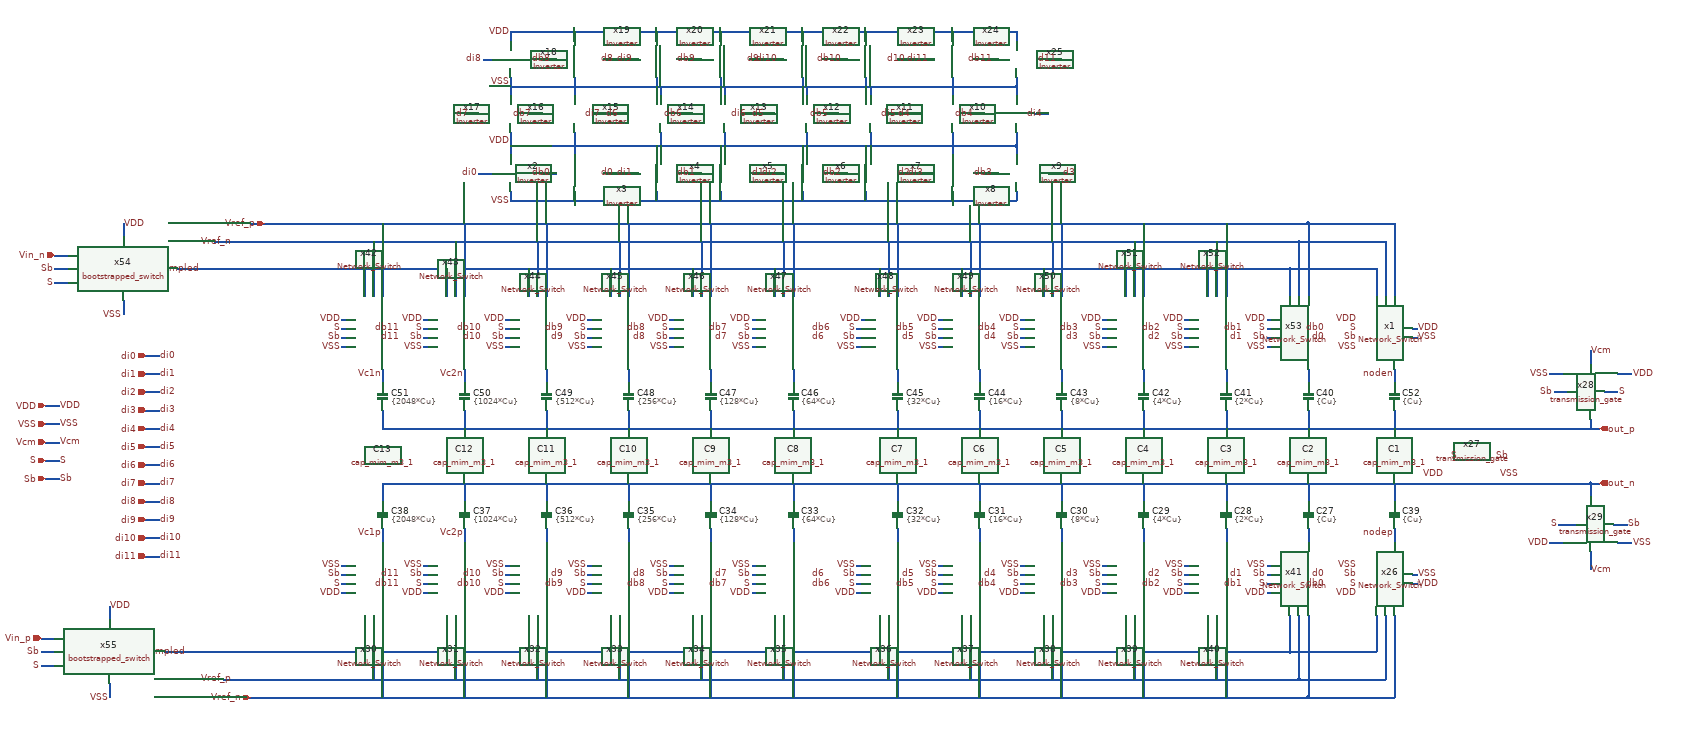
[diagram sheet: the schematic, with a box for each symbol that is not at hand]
v {xschem version=3.4.8RC file_version=1.2}
G {}
K {}
V {}
S {}
E {}
N -970 310 -970 340 {lab=out_n}
N -710 310 10 310 {lab=out_n}
N 90 310 810 310 {lab=out_n}
N 1060 310 1060 340 {lab=out_n}
N 880 310 880 340 {lab=out_n}
N 700 310 700 340 {lab=out_n}
N 520 310 520 340 {lab=out_n}
N 340 310 340 340 {lab=out_n}
N 160 310 160 340 {lab=out_n}
N -70 310 -70 340 {lab=out_n}
N -250 310 -250 340 {lab=out_n}
N -430 310 -430 340 {lab=out_n}
N -610 310 -610 340 {lab=out_n}
N -790 310 -790 340 {lab=out_n}
N -970 160 -970 190 {lab=out_p}
N -710 190 10 190 {lab=out_p}
N 90 190 810 190 {lab=out_p}
N 340 160 340 190 {lab=out_p}
N 160 160 160 190 {lab=out_p}
N -70 160 -70 190 {lab=out_p}
N -250 160 -250 190 {lab=out_p}
N -430 160 -430 190 {lab=out_p}
N -610 160 -610 190 {lab=out_p}
N -790 160 -790 190 {lab=out_p}
N -840 310 -710 310 {lab=out_n}
N -970 310 -840 310 {lab=out_n}
N 810 310 1530 310 {lab=out_n}
N 810 190 1530 190 {lab=out_p}
N -970 420 -970 440 {lab=Vc1p}
N -790 420 -790 440 {lab=Vc2p}
N -970 190 -710 190 {lab=out_p}
N 1060 60 1060 80 {lab=#net1}
N 880 60 880 80 {lab=#net2}
N 700 60 700 80 {lab=#net3}
N 520 60 520 80 {lab=#net4}
N 340 60 340 80 {lab=#net5}
N 160 60 160 80 {lab=#net6}
N -70 60 -70 80 {lab=#net7}
N -250 60 -250 80 {lab=#net8}
N -430 60 -430 80 {lab=#net9}
N -610 60 -610 80 {lab=#net10}
N -790 60 -790 80 {lab=Vc2n}
N -970 60 -970 80 {lab=Vc1n}
N -1010 -160 1020 -160 {lab=in_n_sampled}
N 1020 -160 1020 -100 {lab=in_n_sampled}
N 840 -160 840 -100 {lab=in_n_sampled}
N 660 -160 660 -100 {lab=in_n_sampled}
N 480 -160 480 -100 {lab=in_n_sampled}
N 300 -160 300 -100 {lab=in_n_sampled}
N 120 -160 120 -100 {lab=in_n_sampled}
N -1110 680 1020 680 {lab=in_p_sampled}
N 1020 600 1020 680 {lab=in_p_sampled}
N 840 600 840 680 {lab=in_p_sampled}
N 660 600 660 680 {lab=in_p_sampled}
N 480 600 480 680 {lab=in_p_sampled}
N 300 600 300 680 {lab=in_p_sampled}
N 120 600 120 680 {lab=in_p_sampled}
N -1710 180 -1680 180 {lab=VSS}
N -1710 140 -1680 140 {lab=VDD}
N -1710 260 -1680 260 {lab=S}
N -1710 300 -1680 300 {lab=Sb}
N -1490 150 -1460 150 {lab=di3}
N -1710 220 -1680 220 {lab=Vcm}
N -1540 -260 -1540 -230 {lab=VDD}
N -1570 580 -1570 610 {lab=VDD}
N -1060 -50 -1050 -50 {lab=VDD}
N -880 -50 -870 -50 {lab=VDD}
N -700 -50 -690 -50 {lab=VDD}
N -520 -50 -510 -50 {lab=VDD}
N -340 -50 -330 -50 {lab=VDD}
N -160 -50 -150 -50 {lab=VDD}
N 80 -50 90 -50 {lab=VDD}
N 250 -50 260 -50 {lab=VDD}
N 430 -50 440 -50 {lab=VDD}
N 610 -50 620 -50 {lab=VDD}
N 790 -50 800 -50 {lab=VDD}
N 970 -50 980 -50 {lab=VDD}
N -1060 550 -1050 550 {lab=VDD}
N -880 550 -870 550 {lab=VDD}
N -700 550 -690 550 {lab=VDD}
N -520 550 -510 550 {lab=VDD}
N -340 550 -330 550 {lab=VDD}
N -160 550 -150 550 {lab=VDD}
N 70 550 80 550 {lab=VDD}
N 250 550 260 550 {lab=VDD}
N 430 550 440 550 {lab=VDD}
N 790 550 800 550 {lab=VDD}
N 610 550 620 550 {lab=VDD}
N 970 550 980 550 {lab=VDD}
N -1540 -90 -1540 -60 {lab=VSS}
N -1570 750 -1570 780 {lab=VSS}
N -1060 490 -1050 490 {lab=VSS}
N -880 490 -870 490 {lab=VSS}
N -700 490 -690 490 {lab=VSS}
N -520 490 -510 490 {lab=VSS}
N -340 490 -330 490 {lab=VSS}
N -160 490 -150 490 {lab=VSS}
N 70 490 80 490 {lab=VSS}
N 250 490 260 490 {lab=VSS}
N 430 490 440 490 {lab=VSS}
N 610 490 620 490 {lab=VSS}
N 790 490 800 490 {lab=VSS}
N 970 490 980 490 {lab=VSS}
N -1060 10 -1050 10 {lab=VSS}
N -880 10 -870 10 {lab=VSS}
N -700 10 -690 10 {lab=VSS}
N -520 10 -510 10 {lab=VSS}
N -340 10 -330 10 {lab=VSS}
N -160 10 -150 10 {lab=VSS}
N 70 10 80 10 {lab=VSS}
N 250 10 260 10 {lab=VSS}
N 430 10 440 10 {lab=VSS}
N 610 10 620 10 {lab=VSS}
N 790 10 800 10 {lab=VSS}
N 970 10 980 10 {lab=VSS}
N -1090 -220 1040 -220 {lab=Vref_n}
N 1040 -220 1040 -100 {lab=Vref_n}
N 1060 -260 1060 -100 {lab=Vref_p}
N -1110 -260 1060 -260 {lab=Vref_p}
N -990 -220 -990 -100 {lab=Vref_n}
N -970 -260 -970 -100 {lab=Vref_p}
N -810 -220 -810 -100 {lab=Vref_n}
N -790 -260 -790 -100 {lab=Vref_p}
N -630 -220 -630 -100 {lab=Vref_n}
N -610 -260 -610 -100 {lab=Vref_p}
N -450 -220 -450 -100 {lab=Vref_n}
N -430 -260 -430 -100 {lab=Vref_p}
N -270 -220 -270 -100 {lab=Vref_n}
N -250 -260 -250 -100 {lab=Vref_p}
N -90 -220 -90 -100 {lab=Vref_n}
N -70 -260 -70 -100 {lab=Vref_p}
N 140 -220 140 -100 {lab=Vref_n}
N 160 -260 160 -100 {lab=Vref_p}
N 320 -220 320 -100 {lab=Vref_n}
N 340 -260 340 -100 {lab=Vref_p}
N 500 -220 500 -100 {lab=Vref_n}
N 520 -260 520 -100 {lab=Vref_p}
N 680 -220 680 -100 {lab=Vref_n}
N 700 -260 700 -100 {lab=Vref_p}
N 860 -220 860 -100 {lab=Vref_n}
N 880 -260 880 -100 {lab=Vref_p}
N 1040 600 1040 740 {lab=Vref_p}
N -1090 740 1040 740 {lab=Vref_p}
N 1060 600 1060 780 {lab=Vref_n}
N -1110 780 1060 780 {lab=Vref_n}
N -990 600 -990 740 {lab=Vref_p}
N -970 600 -970 780 {lab=Vref_n}
N -810 600 -810 740 {lab=Vref_p}
N -790 600 -790 780 {lab=Vref_n}
N -630 600 -630 740 {lab=Vref_p}
N -610 600 -610 780 {lab=Vref_n}
N -450 600 -450 740 {lab=Vref_p}
N -430 600 -430 780 {lab=Vref_n}
N -270 600 -270 740 {lab=Vref_p}
N -250 600 -250 780 {lab=Vref_n}
N -90 600 -90 740 {lab=Vref_p}
N -70 600 -70 780 {lab=Vref_n}
N 140 600 140 740 {lab=Vref_p}
N 160 600 160 780 {lab=Vref_n}
N 320 600 320 740 {lab=Vref_p}
N 340 600 340 780 {lab=Vref_n}
N 500 600 500 740 {lab=Vref_p}
N 520 600 520 780 {lab=Vref_n}
N 680 600 680 740 {lab=Vref_p}
N 700 600 700 780 {lab=Vref_n}
N 860 600 860 740 {lab=Vref_p}
N 880 600 880 780 {lab=Vref_n}
N -1490 30 -1460 30 {lab=di0}
N -1490 70 -1460 70 {lab=di1}
N -1490 110 -1460 110 {lab=di2}
N -1490 230 -1460 230 {lab=di5}
N -1490 190 -1460 190 {lab=di4}
N -1490 310 -1460 310 {lab=di7}
N -1490 270 -1460 270 {lab=di6}
N -1490 390 -1460 390 {lab=di9}
N -1490 350 -1460 350 {lab=di8}
N -1490 470 -1460 470 {lab=di11}
N -1490 430 -1460 430 {lab=di10}
N -1060 -30 -1050 -30 {lab=S}
N -1060 -10 -1050 -10 {lab=Sb}
N -880 -30 -870 -30 {lab=S}
N -880 -10 -870 -10 {lab=Sb}
N -700 -30 -690 -30 {lab=S}
N -700 -10 -690 -10 {lab=Sb}
N -520 -30 -510 -30 {lab=S}
N -520 -10 -510 -10 {lab=Sb}
N -340 -30 -330 -30 {lab=S}
N -340 -10 -330 -10 {lab=Sb}
N -160 -30 -150 -30 {lab=S}
N -160 -10 -150 -10 {lab=Sb}
N 70 -30 80 -30 {lab=S}
N 70 -10 80 -10 {lab=Sb}
N 250 -30 260 -30 {lab=S}
N 250 -10 260 -10 {lab=Sb}
N 430 -30 440 -30 {lab=S}
N 430 -10 440 -10 {lab=Sb}
N 610 -30 620 -30 {lab=S}
N 610 -10 620 -10 {lab=Sb}
N 790 -30 800 -30 {lab=S}
N 790 -10 800 -10 {lab=Sb}
N 970 -30 980 -30 {lab=S}
N 970 -10 980 -10 {lab=Sb}
N -1060 530 -1050 530 {lab=S}
N -1060 510 -1050 510 {lab=Sb}
N -880 530 -870 530 {lab=S}
N -880 510 -870 510 {lab=Sb}
N -700 530 -690 530 {lab=S}
N -700 510 -690 510 {lab=Sb}
N -520 530 -510 530 {lab=S}
N -520 510 -510 510 {lab=Sb}
N -340 530 -330 530 {lab=S}
N -340 510 -330 510 {lab=Sb}
N -160 530 -150 530 {lab=S}
N -160 510 -150 510 {lab=Sb}
N 70 530 80 530 {lab=S}
N 70 510 80 510 {lab=Sb}
N 250 530 260 530 {lab=S}
N 250 510 260 510 {lab=Sb}
N 430 530 440 530 {lab=S}
N 430 510 440 510 {lab=Sb}
N 610 530 620 530 {lab=S}
N 610 510 620 510 {lab=Sb}
N 790 530 800 530 {lab=S}
N 790 510 800 510 {lab=Sb}
N 970 530 980 530 {lab=S}
N 970 510 980 510 {lab=Sb}
N -1690 -190 -1660 -190 {lab=Vin_n}
N -1720 650 -1690 650 {lab=Vin_p}
N -1690 -130 -1660 -130 {lab=S}
N -1690 -160 -1660 -160 {lab=Sb}
N -1720 710 -1690 710 {lab=S}
N -1720 680 -1690 680 {lab=Sb}
N -970 80 -970 90 {lab=Vc1n}
N -970 150 -970 160 {lab=out_p}
N 160 150 160 160 {lab=out_p}
N -790 80 -790 90 {lab=Vc2n}
N -790 150 -790 160 {lab=out_p}
N -610 150 -610 160 {lab=out_p}
N -610 80 -610 90 {lab=#net10}
N -430 80 -430 90 {lab=#net9}
N -430 150 -430 160 {lab=out_p}
N -250 150 -250 160 {lab=out_p}
N -250 80 -250 90 {lab=#net8}
N -70 80 -70 90 {lab=#net7}
N -70 150 -70 160 {lab=out_p}
N 10 190 20 190 {lab=out_p}
N 80 190 90 190 {lab=out_p}
N 160 80 160 90 {lab=#net6}
N 340 150 340 160 {lab=out_p}
N 340 80 340 90 {lab=#net5}
N 520 80 520 90 {lab=#net4}
N 700 80 700 90 {lab=#net3}
N 880 80 880 90 {lab=#net2}
N 1060 80 1060 90 {lab=#net1}
N 1060 340 1060 350 {lab=out_n}
N 880 340 880 350 {lab=out_n}
N 700 340 700 350 {lab=out_n}
N 520 340 520 350 {lab=out_n}
N 340 340 340 350 {lab=out_n}
N 160 340 160 350 {lab=out_n}
N 80 310 90 310 {lab=out_n}
N 10 310 20 310 {lab=out_n}
N -970 340 -970 350 {lab=out_n}
N -970 410 -970 420 {lab=Vc1p}
N -790 410 -790 420 {lab=Vc2p}
N -790 340 -790 350 {lab=out_n}
N -610 340 -610 350 {lab=out_n}
N -430 340 -430 350 {lab=out_n}
N -70 340 -70 350 {lab=out_n}
N -250 340 -250 350 {lab=out_n}
N -1190 -260 -1110 -260 {lab=Vref_p}
N -1260 -260 -1190 -260 {lab=Vref_p}
N 1250 310 1250 350 {lab=out_n}
N -1190 780 -1110 780 {lab=Vref_n}
N -1270 780 -1190 780 {lab=Vref_n}
N -690 -460 -690 -410 {lab=VDD}
N -690 -430 420 -430 {lab=VDD}
N 420 -430 420 -410 {lab=VDD}
N 420 -450 420 -430 {lab=VDD}
N 420 -460 420 -450 {lab=VDD}
N 280 -460 280 -430 {lab=VDD}
N 280 -430 280 -420 {lab=VDD}
N 280 -420 280 -410 {lab=VDD}
N 90 -430 90 -410 {lab=VDD}
N 100 -460 100 -430 {lab=VDD}
N -50 -430 -50 -410 {lab=VDD}
N -230 -430 -230 -410 {lab=VDD}
N -370 -430 -370 -410 {lab=VDD}
N -40 -460 -40 -430 {lab=VDD}
N -220 -460 -220 -430 {lab=VDD}
N -360 -460 -360 -430 {lab=VDD}
N -550 -460 -550 -430 {lab=VDD}
N -550 -430 -550 -410 {lab=VDD}
N -690 -580 -690 -540 {lab=VSS}
N -690 -560 420 -560 {lab=VSS}
N 420 -560 420 -540 {lab=VSS}
N 420 -580 420 -560 {lab=VSS}
N 280 -580 280 -560 {lab=VSS}
N 280 -560 280 -540 {lab=VSS}
N 100 -560 100 -540 {lab=VSS}
N 90 -580 90 -560 {lab=VSS}
N -40 -560 -40 -540 {lab=VSS}
N -50 -580 -50 -560 {lab=VSS}
N -230 -580 -230 -560 {lab=VSS}
N -220 -560 -220 -540 {lab=VSS}
N -360 -560 -360 -540 {lab=VSS}
N -370 -580 -370 -560 {lab=VSS}
N -550 -580 -550 -560 {lab=VSS}
N -550 -560 -550 -540 {lab=VSS}
N -690 -680 -690 -660 {lab=VDD}
N -690 -680 420 -680 {lab=VDD}
N 420 -680 420 -660 {lab=VDD}
N 280 -680 280 -660 {lab=VDD}
N 90 -680 90 -660 {lab=VDD}
N -50 -680 -50 -660 {lab=VDD}
N -550 -680 -550 -660 {lab=VDD}
N -370 -680 -370 -660 {lab=VDD}
N -230 -680 -230 -660 {lab=VDD}
N -620 -370 -590 -370 {lab=db0}
N -470 -370 -460 -370 {lab=d0}
N -480 -370 -470 -370 {lab=d0}
N -430 -370 -410 -370 {lab=di1}
N -290 -370 -270 -370 {lab=db1}
N -300 -370 -290 -370 {lab=db1}
N -760 -370 -730 -370 {lab=di0}
N -650 -500 -620 -500 {lab=db7}
N -510 -500 -480 -500 {lab=di7}
N -790 -500 -770 -500 {lab=d7}
N -460 -500 -440 -500 {lab=d6}
N -440 -500 -430 -500 {lab=d6}
N -320 -500 -290 -500 {lab=db6}
N -180 -500 -160 -500 {lab=di6}
N -130 -500 -110 -500 {lab=d5}
N -160 -370 -130 -370 {lab=d1}
N -110 -370 -90 -370 {lab=di2}
N 20 -370 50 -370 {lab=db2}
N 160 -370 190 -370 {lab=d2}
N 220 -370 240 -370 {lab=di3}
N 0 -500 20 -500 {lab=db5}
N 140 -500 160 -500 {lab=di5}
N 180 -500 200 -500 {lab=d4}
N 320 -500 350 -500 {lab=db4}
N 460 -500 490 -500 {lab=di4}
N 500 -370 530 -370 {lab=d3}
N 490 -370 500 -370 {lab=d3}
N 350 -370 380 -370 {lab=db3}
N 420 -330 420 -310 {lab=VSS}
N -690 -310 420 -310 {lab=VSS}
N -690 -330 -690 -310 {lab=VSS}
N -550 -330 -550 -310 {lab=VSS}
N -370 -330 -370 -310 {lab=VSS}
N -230 -330 -230 -310 {lab=VSS}
N 280 -330 280 -310 {lab=VSS}
N 90 -330 90 -310 {lab=VSS}
N -50 -330 -50 -310 {lab=VSS}
N 500 -620 520 -620 {lab=d11}
N 490 -620 500 -620 {lab=d11}
N 350 -620 380 -620 {lab=db11}
N 220 -620 240 -620 {lab=di11}
N 20 -620 50 -620 {lab=db10}
N 160 -620 190 -620 {lab=d10}
N -110 -620 -90 -620 {lab=di10}
N -160 -620 -130 -620 {lab=d9}
N -620 -620 -590 -620 {lab=db8}
N -480 -620 -450 -620 {lab=d8}
N -430 -620 -410 -620 {lab=di9}
N -300 -620 -270 -620 {lab=db9}
N -750 -620 -730 -620 {lab=di8}
N -770 -500 -760 -500 {lab=d7}
N 200 -500 210 -500 {lab=d4}
N 20 -500 30 -500 {lab=db5}
N -1010 -120 -1010 -100 {lab=in_n_sampled}
N -830 -120 -830 -100 {lab=in_n_sampled}
N -650 -120 -650 -100 {lab=in_n_sampled}
N -470 -120 -470 -100 {lab=in_n_sampled}
N -290 -130 -290 -100 {lab=in_n_sampled}
N -110 -120 -110 -100 {lab=in_n_sampled}
N -1010 600 -1010 630 {lab=in_p_sampled}
N -830 600 -830 630 {lab=in_p_sampled}
N -650 600 -650 630 {lab=in_p_sampled}
N -470 600 -470 630 {lab=in_p_sampled}
N -290 600 -290 630 {lab=in_p_sampled}
N -110 600 -110 630 {lab=in_p_sampled}
N -1010 -160 -1010 -120 {lab=in_n_sampled}
N -830 -160 -830 -120 {lab=in_n_sampled}
N -650 -160 -650 -120 {lab=in_n_sampled}
N -470 -160 -470 -120 {lab=in_n_sampled}
N -110 -160 -110 -120 {lab=in_n_sampled}
N -290 -160 -290 -130 {lab=in_n_sampled}
N -1010 630 -1010 680 {lab=in_p_sampled}
N -830 630 -830 680 {lab=in_p_sampled}
N -650 630 -650 680 {lab=in_p_sampled}
N -470 630 -470 670 {lab=in_p_sampled}
N -470 670 -470 680 {lab=in_p_sampled}
N -290 630 -290 680 {lab=in_p_sampled}
N -110 630 -110 680 {lab=in_p_sampled}
N 1680 20 1680 50 {lab=Vcm}
N 1680 170 1680 190 {lab=out_p}
N 1680 310 1680 340 {lab=out_n}
N 1710 110 1740 110 {lab=S}
N 1600 110 1630 110 {lab=Sb}
N 1590 70 1620 70 {lab=VSS}
N 1740 70 1770 70 {lab=VDD}
N 1730 400 1760 400 {lab=Sb}
N 1610 400 1650 400 {lab=S}
N 1680 460 1680 480 {lab=Vcm}
N 1740 440 1770 440 {lab=VSS}
N 1590 440 1620 440 {lab=VDD}
N 1680 480 1680 500 {lab=Vcm}
N 20 190 80 190 {lab=out_p}
N 20 310 80 310 {lab=out_n}
N 520 150 520 190 {lab=out_p}
N 700 150 700 190 {lab=out_p}
N 880 150 880 190 {lab=out_p}
N 1060 150 1060 190 {lab=out_p}
N -610 410 -610 440 {lab=#net11}
N -430 410 -430 440 {lab=#net12}
N -250 410 -250 440 {lab=#net13}
N -70 410 -70 440 {lab=#net14}
N 160 410 160 440 {lab=#net15}
N 340 410 340 440 {lab=#net16}
N 520 410 520 440 {lab=#net17}
N 700 410 700 440 {lab=#net18}
N 880 410 880 440 {lab=#net19}
N 1060 410 1060 440 {lab=#net20}
N 1250 60 1250 90 {lab=noden}
N 1290 -30 1300 -30 {lab=VDD}
N 1290 -10 1300 -10 {lab=VSS}
N -1340 -220 -1090 -220 {lab=Vref_n}
N 1230 -220 1230 -100 {lab=Vref_n}
N 1250 -260 1250 -100 {lab=Vref_p}
N 1210 -160 1210 -100 {lab=in_n_sampled}
N 1290 530 1300 530 {lab=VDD}
N 1290 510 1300 510 {lab=VSS}
N 1250 410 1250 440 {lab=nodep}
N -1320 740 -1090 740 {lab=Vref_p}
N 1250 600 1250 780 {lab=Vref_n}
N 1230 600 1230 740 {lab=Vref_p}
N -1450 680 -1110 680 {lab=in_p_sampled}
N 1210 600 1210 680 {lab=in_p_sampled}
N 1530 190 1680 190 {lab=out_p}
N 1530 310 1680 310 {lab=out_n}
N 1680 310 1700 310 {lab=out_n}
N 1680 190 1700 190 {lab=out_p}
N -1420 -160 -1390 -160 {lab=in_n_sampled}
N -1390 -160 -1010 -160 {lab=in_n_sampled}
N 1060 -260 1250 -260 {lab=Vref_p}
N 1040 -220 1230 -220 {lab=Vref_n}
N 1020 -160 1210 -160 {lab=in_n_sampled}
N 1250 150 1250 190 {lab=out_p}
N 1060 780 1250 780 {lab=Vref_n}
N 1040 740 1230 740 {lab=Vref_p}
N 1020 680 1210 680 {lab=in_p_sampled}
C {Network_Switch.sym} -990 520 2 1 {name=x30}
C {Network_Switch.sym} -810 520 2 1 {name=x31}
C {Network_Switch.sym} -630 520 2 1 {name=x32}
C {Network_Switch.sym} -450 520 2 1 {name=x33}
C {Network_Switch.sym} -270 520 2 1 {name=x34}
C {Network_Switch.sym} -90 520 2 1 {name=x35}
C {Network_Switch.sym} 140 520 2 1 {name=x36}
C {Network_Switch.sym} 320 520 2 1 {name=x37}
C {Network_Switch.sym} 500 520 2 1 {name=x38}
C {Network_Switch.sym} 680 520 2 1 {name=x39}
C {Network_Switch.sym} 860 520 2 1 {name=x40}
C {Network_Switch.sym} 1040 520 2 1 {name=x41}
C {Network_Switch.sym} -990 -20 0 0 {name=x42}
C {Network_Switch.sym} -810 -20 0 0 {name=x43}
C {Network_Switch.sym} -630 -20 0 0 {name=x44}
C {Network_Switch.sym} -450 -20 0 0 {name=x45}
C {Network_Switch.sym} -270 -20 0 0 {name=x46}
C {Network_Switch.sym} -90 -20 0 0 {name=x47}
C {Network_Switch.sym} 140 -20 0 0 {name=x48}
C {Network_Switch.sym} 320 -20 0 0 {name=x49}
C {Network_Switch.sym} 500 -20 0 0 {name=x50}
C {Network_Switch.sym} 680 -20 0 0 {name=x51}
C {Network_Switch.sym} 860 -20 0 0 {name=x52}
C {Network_Switch.sym} 1040 -20 0 0 {name=x53}
C {devices/ipin.sym} -1710 140 0 0 {name=p5 lab=VDD}
C {devices/ipin.sym} -1710 180 0 0 {name=p6 lab=VSS}
C {devices/ipin.sym} -1710 260 0 0 {name=p7 lab=S}
C {devices/lab_pin.sym} -1680 140 2 0 {name=p8 sig_type=std_logic lab=VDD}
C {devices/lab_pin.sym} -1680 180 2 0 {name=p9 sig_type=std_logic lab=VSS}
C {devices/ipin.sym} -1710 300 0 0 {name=p18 lab=Sb}
C {devices/ipin.sym} -1490 150 0 0 {name=p19 lab=di3}
C {devices/lab_pin.sym} -1680 260 2 0 {name=p21 sig_type=std_logic lab=S}
C {devices/lab_pin.sym} -1680 300 2 0 {name=p22 sig_type=std_logic lab=Sb}
C {devices/lab_pin.sym} -1460 150 2 0 {name=p27 sig_type=std_logic lab=di3}
C {devices/ipin.sym} -1710 220 0 0 {name=p1 lab=Vcm}
C {devices/lab_pin.sym} -1680 220 2 0 {name=p2 sig_type=std_logic lab=Vcm}
C {devices/lab_pin.sym} -1540 -260 2 0 {name=p3 sig_type=std_logic lab=VDD}
C {devices/lab_pin.sym} -1570 580 2 0 {name=p4 sig_type=std_logic lab=VDD}
C {devices/lab_pin.sym} -1060 -50 0 0 {name=p10 sig_type=std_logic lab=VDD}
C {devices/lab_pin.sym} -880 -50 0 0 {name=p11 sig_type=std_logic lab=VDD}
C {devices/lab_pin.sym} -700 -50 0 0 {name=p12 sig_type=std_logic lab=VDD}
C {devices/lab_pin.sym} -520 -50 0 0 {name=p13 sig_type=std_logic lab=VDD}
C {devices/lab_pin.sym} -340 -50 0 0 {name=p14 sig_type=std_logic lab=VDD}
C {devices/lab_pin.sym} -160 -50 0 0 {name=p15 sig_type=std_logic lab=VDD}
C {devices/lab_pin.sym} 80 -50 0 0 {name=p16 sig_type=std_logic lab=VDD}
C {devices/lab_pin.sym} 250 -50 0 0 {name=p17 sig_type=std_logic lab=VDD}
C {devices/lab_pin.sym} 430 -50 0 0 {name=p23 sig_type=std_logic lab=VDD}
C {devices/lab_pin.sym} 610 -50 0 0 {name=p24 sig_type=std_logic lab=VDD}
C {devices/lab_pin.sym} 790 -50 0 0 {name=p25 sig_type=std_logic lab=VDD}
C {devices/lab_pin.sym} 970 -50 0 0 {name=p26 sig_type=std_logic lab=VDD}
C {devices/lab_pin.sym} -1060 550 0 0 {name=p29 sig_type=std_logic lab=VDD}
C {devices/lab_pin.sym} -880 550 0 0 {name=p30 sig_type=std_logic lab=VDD}
C {devices/lab_pin.sym} -700 550 0 0 {name=p31 sig_type=std_logic lab=VDD}
C {devices/lab_pin.sym} -520 550 0 0 {name=p32 sig_type=std_logic lab=VDD}
C {devices/lab_pin.sym} -340 550 0 0 {name=p33 sig_type=std_logic lab=VDD}
C {devices/lab_pin.sym} -160 550 0 0 {name=p34 sig_type=std_logic lab=VDD}
C {devices/lab_pin.sym} 70 550 0 0 {name=p35 sig_type=std_logic lab=VDD}
C {devices/lab_pin.sym} 250 550 0 0 {name=p36 sig_type=std_logic lab=VDD}
C {devices/lab_pin.sym} 430 550 0 0 {name=p37 sig_type=std_logic lab=VDD}
C {devices/lab_pin.sym} 790 550 0 0 {name=p38 sig_type=std_logic lab=VDD}
C {devices/lab_pin.sym} 610 550 0 0 {name=p39 sig_type=std_logic lab=VDD}
C {devices/lab_pin.sym} 970 550 0 0 {name=p40 sig_type=std_logic lab=VDD}
C {devices/lab_pin.sym} -1540 -60 0 0 {name=p44 sig_type=std_logic lab=VSS}
C {devices/lab_pin.sym} -1570 780 0 0 {name=p45 sig_type=std_logic lab=VSS}
C {devices/lab_pin.sym} -1060 490 0 0 {name=p46 sig_type=std_logic lab=VSS}
C {devices/lab_pin.sym} -880 490 0 0 {name=p47 sig_type=std_logic lab=VSS}
C {devices/lab_pin.sym} -700 490 0 0 {name=p48 sig_type=std_logic lab=VSS}
C {devices/lab_pin.sym} -520 490 0 0 {name=p49 sig_type=std_logic lab=VSS}
C {devices/lab_pin.sym} -340 490 0 0 {name=p50 sig_type=std_logic lab=VSS}
C {devices/lab_pin.sym} -160 490 0 0 {name=p51 sig_type=std_logic lab=VSS}
C {devices/lab_pin.sym} 70 490 0 0 {name=p52 sig_type=std_logic lab=VSS}
C {devices/lab_pin.sym} 250 490 0 0 {name=p53 sig_type=std_logic lab=VSS}
C {devices/lab_pin.sym} 430 490 0 0 {name=p54 sig_type=std_logic lab=VSS}
C {devices/lab_pin.sym} 610 490 0 0 {name=p55 sig_type=std_logic lab=VSS}
C {devices/lab_pin.sym} 790 490 0 0 {name=p56 sig_type=std_logic lab=VSS}
C {devices/lab_pin.sym} 970 490 0 0 {name=p57 sig_type=std_logic lab=VSS}
C {devices/lab_pin.sym} -1060 10 0 0 {name=p58 sig_type=std_logic lab=VSS}
C {devices/lab_pin.sym} -880 10 0 0 {name=p59 sig_type=std_logic lab=VSS}
C {devices/lab_pin.sym} -700 10 0 0 {name=p60 sig_type=std_logic lab=VSS}
C {devices/lab_pin.sym} -520 10 0 0 {name=p61 sig_type=std_logic lab=VSS}
C {devices/lab_pin.sym} -340 10 0 0 {name=p62 sig_type=std_logic lab=VSS}
C {devices/lab_pin.sym} -160 10 0 0 {name=p63 sig_type=std_logic lab=VSS}
C {devices/lab_pin.sym} 70 10 0 0 {name=p64 sig_type=std_logic lab=VSS}
C {devices/lab_pin.sym} 250 10 0 0 {name=p65 sig_type=std_logic lab=VSS}
C {devices/lab_pin.sym} 430 10 0 0 {name=p66 sig_type=std_logic lab=VSS}
C {devices/lab_pin.sym} 610 10 0 0 {name=p67 sig_type=std_logic lab=VSS}
C {devices/lab_pin.sym} 790 10 0 0 {name=p68 sig_type=std_logic lab=VSS}
C {devices/lab_pin.sym} 970 10 0 0 {name=p69 sig_type=std_logic lab=VSS}
C {devices/opin.sym} 1700 190 0 0 {name=p76 lab=out_p}
C {devices/opin.sym} 1700 310 0 0 {name=p77 lab=out_n
}
C {devices/ipin.sym} -1230 -260 0 0 {name=p78 lab=Vref_p}
C {devices/ipin.sym} -1260 780 0 0 {name=p79 lab=Vref_n}
C {devices/lab_pin.sym} -1300 740 0 0 {name=p80 sig_type=std_logic lab=Vref_p}
C {devices/lab_pin.sym} -1300 -220 0 0 {name=p81 sig_type=std_logic lab=Vref_n}
C {devices/ipin.sym} -1490 30 0 0 {name=p82 lab=di0}
C {devices/lab_pin.sym} -1460 30 2 0 {name=p84 sig_type=std_logic lab=di0}
C {devices/ipin.sym} -1490 70 0 0 {name=p86 lab=di1}
C {devices/lab_pin.sym} -1460 70 2 0 {name=p88 sig_type=std_logic lab=di1}
C {devices/ipin.sym} -1490 110 0 0 {name=p90 lab=di2}
C {devices/lab_pin.sym} -1460 110 2 0 {name=p92 sig_type=std_logic lab=di2}
C {devices/ipin.sym} -1490 230 0 0 {name=p94 lab=di5}
C {devices/lab_pin.sym} -1460 230 2 0 {name=p96 sig_type=std_logic lab=di5}
C {devices/ipin.sym} -1490 190 0 0 {name=p98 lab=di4}
C {devices/lab_pin.sym} -1460 190 2 0 {name=p100 sig_type=std_logic lab=di4}
C {devices/ipin.sym} -1490 310 0 0 {name=p102 lab=di7}
C {devices/lab_pin.sym} -1460 310 2 0 {name=p104 sig_type=std_logic lab=di7}
C {devices/ipin.sym} -1490 270 0 0 {name=p106 lab=di6}
C {devices/lab_pin.sym} -1460 270 2 0 {name=p108 sig_type=std_logic lab=di6}
C {devices/ipin.sym} -1490 390 0 0 {name=p110 lab=di9}
C {devices/lab_pin.sym} -1460 390 2 0 {name=p112 sig_type=std_logic lab=di9}
C {devices/ipin.sym} -1490 350 0 0 {name=p114 lab=di8}
C {devices/lab_pin.sym} -1460 350 2 0 {name=p116 sig_type=std_logic lab=di8}
C {devices/ipin.sym} -1490 470 0 0 {name=p118 lab=di11}
C {devices/lab_pin.sym} -1460 470 2 0 {name=p120 sig_type=std_logic lab=di11}
C {devices/ipin.sym} -1490 430 0 0 {name=p122 lab=di10}
C {devices/lab_pin.sym} -1460 430 2 0 {name=p124 sig_type=std_logic lab=di10}
C {devices/lab_pin.sym} -1060 -30 2 1 {name=p126 sig_type=std_logic lab=S}
C {devices/lab_pin.sym} -1060 -10 2 1 {name=p127 sig_type=std_logic lab=Sb}
C {devices/lab_pin.sym} -880 -30 2 1 {name=p128 sig_type=std_logic lab=S}
C {devices/lab_pin.sym} -880 -10 2 1 {name=p129 sig_type=std_logic lab=Sb}
C {devices/lab_pin.sym} -700 -30 2 1 {name=p130 sig_type=std_logic lab=S}
C {devices/lab_pin.sym} -700 -10 2 1 {name=p131 sig_type=std_logic lab=Sb}
C {devices/lab_pin.sym} -520 -30 2 1 {name=p132 sig_type=std_logic lab=S}
C {devices/lab_pin.sym} -520 -10 2 1 {name=p133 sig_type=std_logic lab=Sb}
C {devices/lab_pin.sym} -340 -30 2 1 {name=p134 sig_type=std_logic lab=S}
C {devices/lab_pin.sym} -340 -10 2 1 {name=p135 sig_type=std_logic lab=Sb}
C {devices/lab_pin.sym} -160 -30 2 1 {name=p136 sig_type=std_logic lab=S}
C {devices/lab_pin.sym} -160 -10 2 1 {name=p137 sig_type=std_logic lab=Sb}
C {devices/lab_pin.sym} 70 -30 2 1 {name=p138 sig_type=std_logic lab=S}
C {devices/lab_pin.sym} 70 -10 2 1 {name=p139 sig_type=std_logic lab=Sb}
C {devices/lab_pin.sym} 250 -30 2 1 {name=p140 sig_type=std_logic lab=S}
C {devices/lab_pin.sym} 250 -10 2 1 {name=p141 sig_type=std_logic lab=Sb}
C {devices/lab_pin.sym} 430 -30 2 1 {name=p142 sig_type=std_logic lab=S}
C {devices/lab_pin.sym} 430 -10 2 1 {name=p143 sig_type=std_logic lab=Sb}
C {devices/lab_pin.sym} 610 -30 2 1 {name=p144 sig_type=std_logic lab=S}
C {devices/lab_pin.sym} 610 -10 2 1 {name=p145 sig_type=std_logic lab=Sb}
C {devices/lab_pin.sym} 790 -30 2 1 {name=p146 sig_type=std_logic lab=S}
C {devices/lab_pin.sym} 790 -10 2 1 {name=p147 sig_type=std_logic lab=Sb}
C {devices/lab_pin.sym} 970 -30 2 1 {name=p148 sig_type=std_logic lab=S}
C {devices/lab_pin.sym} 970 -10 2 1 {name=p149 sig_type=std_logic lab=Sb}
C {devices/lab_pin.sym} -1060 530 2 1 {name=p152 sig_type=std_logic lab=S}
C {devices/lab_pin.sym} -1060 510 2 1 {name=p153 sig_type=std_logic lab=Sb}
C {devices/lab_pin.sym} -880 530 2 1 {name=p150 sig_type=std_logic lab=S}
C {devices/lab_pin.sym} -880 510 2 1 {name=p151 sig_type=std_logic lab=Sb}
C {devices/lab_pin.sym} -700 530 2 1 {name=p154 sig_type=std_logic lab=S}
C {devices/lab_pin.sym} -700 510 2 1 {name=p155 sig_type=std_logic lab=Sb}
C {devices/lab_pin.sym} -520 530 2 1 {name=p156 sig_type=std_logic lab=S}
C {devices/lab_pin.sym} -520 510 2 1 {name=p157 sig_type=std_logic lab=Sb}
C {devices/lab_pin.sym} -340 530 2 1 {name=p158 sig_type=std_logic lab=S}
C {devices/lab_pin.sym} -340 510 2 1 {name=p159 sig_type=std_logic lab=Sb}
C {devices/lab_pin.sym} -160 530 2 1 {name=p160 sig_type=std_logic lab=S}
C {devices/lab_pin.sym} -160 510 2 1 {name=p161 sig_type=std_logic lab=Sb}
C {devices/lab_pin.sym} 70 530 2 1 {name=p162 sig_type=std_logic lab=S}
C {devices/lab_pin.sym} 70 510 2 1 {name=p163 sig_type=std_logic lab=Sb}
C {devices/lab_pin.sym} 250 530 2 1 {name=p164 sig_type=std_logic lab=S}
C {devices/lab_pin.sym} 250 510 2 1 {name=p165 sig_type=std_logic lab=Sb}
C {devices/lab_pin.sym} 430 530 2 1 {name=p166 sig_type=std_logic lab=S}
C {devices/lab_pin.sym} 430 510 2 1 {name=p167 sig_type=std_logic lab=Sb}
C {devices/lab_pin.sym} 610 530 2 1 {name=p168 sig_type=std_logic lab=S}
C {devices/lab_pin.sym} 610 510 2 1 {name=p169 sig_type=std_logic lab=Sb}
C {devices/lab_pin.sym} 790 530 2 1 {name=p170 sig_type=std_logic lab=S}
C {devices/lab_pin.sym} 790 510 2 1 {name=p171 sig_type=std_logic lab=Sb}
C {devices/lab_pin.sym} 970 530 2 1 {name=p172 sig_type=std_logic lab=S}
C {devices/lab_pin.sym} 970 510 2 1 {name=p173 sig_type=std_logic lab=Sb}
C {devices/lab_pin.sym} -930 -10 0 0 {name=p174 sig_type=std_logic lab=d11}
C {devices/lab_pin.sym} -930 -30 0 0 {name=p175 sig_type=std_logic lab=db11}
C {devices/lab_pin.sym} -750 -10 0 0 {name=p176 sig_type=std_logic lab=d10}
C {devices/lab_pin.sym} -750 -30 0 0 {name=p177 sig_type=std_logic lab=db10}
C {devices/lab_pin.sym} -570 -10 0 0 {name=p178 sig_type=std_logic lab=d9}
C {devices/lab_pin.sym} -570 -30 0 0 {name=p179 sig_type=std_logic lab=db9}
C {devices/lab_pin.sym} -930 530 0 0 {name=p180 sig_type=std_logic lab=db11}
C {devices/lab_pin.sym} -930 510 0 0 {name=p181 sig_type=std_logic lab=d11}
C {devices/lab_pin.sym} -750 530 0 0 {name=p182 sig_type=std_logic lab=db10}
C {devices/lab_pin.sym} -750 510 0 0 {name=p183 sig_type=std_logic lab=d10}
C {devices/lab_pin.sym} -570 530 0 0 {name=p184 sig_type=std_logic lab=db9}
C {devices/lab_pin.sym} -570 510 0 0 {name=p185 sig_type=std_logic lab=d9}
C {devices/lab_pin.sym} -390 -10 0 0 {name=p186 sig_type=std_logic lab=d8}
C {devices/lab_pin.sym} -390 510 0 0 {name=p187 sig_type=std_logic lab=d8}
C {devices/lab_pin.sym} -390 -30 0 0 {name=p188 sig_type=std_logic lab=db8}
C {devices/lab_pin.sym} -390 530 0 0 {name=p189 sig_type=std_logic lab=db8}
C {devices/lab_pin.sym} -210 -10 0 0 {name=p190 sig_type=std_logic lab=d7}
C {devices/lab_pin.sym} -210 510 0 0 {name=p191 sig_type=std_logic lab=d7}
C {devices/lab_pin.sym} -210 -30 0 0 {name=p192 sig_type=std_logic lab=db7}
C {devices/lab_pin.sym} -210 530 0 0 {name=p193 sig_type=std_logic lab=db7}
C {devices/lab_pin.sym} -30 -10 2 0 {name=p194 sig_type=std_logic lab=d6}
C {devices/lab_pin.sym} -30 510 2 0 {name=p195 sig_type=std_logic lab=d6}
C {devices/lab_pin.sym} -30 -30 2 0 {name=p196 sig_type=std_logic lab=db6}
C {devices/lab_pin.sym} -30 530 2 0 {name=p197 sig_type=std_logic lab=db6}
C {devices/lab_pin.sym} 200 -10 0 0 {name=p198 sig_type=std_logic lab=d5}
C {devices/lab_pin.sym} 200 510 0 0 {name=p199 sig_type=std_logic lab=d5}
C {devices/lab_pin.sym} 200 -30 0 0 {name=p200 sig_type=std_logic lab=db5}
C {devices/lab_pin.sym} 200 530 0 0 {name=p201 sig_type=std_logic lab=db5}
C {devices/lab_pin.sym} 380 -10 0 0 {name=p202 sig_type=std_logic lab=d4}
C {devices/lab_pin.sym} 380 -30 0 0 {name=p203 sig_type=std_logic lab=db4}
C {devices/lab_pin.sym} 380 530 0 0 {name=p204 sig_type=std_logic lab=db4}
C {devices/lab_pin.sym} 380 510 0 0 {name=p205 sig_type=std_logic lab=d4}
C {devices/lab_pin.sym} 560 510 0 0 {name=p206 sig_type=std_logic lab=d3}
C {devices/lab_pin.sym} 560 530 0 0 {name=p207 sig_type=std_logic lab=db3}
C {devices/lab_pin.sym} 560 -30 0 0 {name=p208 sig_type=std_logic lab=db3}
C {devices/lab_pin.sym} 560 -10 0 0 {name=p209 sig_type=std_logic lab=d3}
C {devices/lab_pin.sym} 740 -10 0 0 {name=p210 sig_type=std_logic lab=d2}
C {devices/lab_pin.sym} 740 -30 0 0 {name=p211 sig_type=std_logic lab=db2}
C {devices/lab_pin.sym} 740 530 0 0 {name=p212 sig_type=std_logic lab=db2}
C {devices/lab_pin.sym} 740 510 0 0 {name=p213 sig_type=std_logic lab=d2}
C {devices/lab_pin.sym} 920 510 0 0 {name=p214 sig_type=std_logic lab=d1}
C {devices/lab_pin.sym} 920 530 0 0 {name=p215 sig_type=std_logic lab=db1}
C {devices/lab_pin.sym} 920 -30 0 0 {name=p216 sig_type=std_logic lab=db1}
C {devices/lab_pin.sym} 920 -10 0 0 {name=p217 sig_type=std_logic lab=d1}
C {devices/lab_pin.sym} 1100 -10 0 0 {name=p218 sig_type=std_logic lab=d0}
C {devices/lab_pin.sym} 1100 510 0 0 {name=p219 sig_type=std_logic lab=d0}
C {devices/lab_pin.sym} 1100 -30 0 0 {name=p220 sig_type=std_logic lab=db0}
C {devices/lab_pin.sym} 1100 530 0 0 {name=p221 sig_type=std_logic lab=db0}
C {devices/ipin.sym} -1690 -190 0 0 {name=p227 lab=Vin_n}
C {devices/ipin.sym} -1720 650 0 0 {name=p228 lab=Vin_p}
C {devices/lab_pin.sym} -1690 -130 0 0 {name=p229 sig_type=std_logic lab=S}
C {devices/lab_pin.sym} -1690 -160 0 0 {name=p230 sig_type=std_logic lab=Sb}
C {devices/lab_pin.sym} -1720 710 0 0 {name=p231 sig_type=std_logic lab=S}
C {devices/lab_pin.sym} -1720 680 0 0 {name=p232 sig_type=std_logic lab=Sb}
C {devices/lab_pin.sym} -1370 -160 3 0 {name=p233 sig_type=std_logic lab=in_n_sampled}
C {devices/lab_pin.sym} -1400 680 1 0 {name=p234 sig_type=std_logic lab=in_p_sampled}
C {transmission_gate.sym} 1420 240 3 0 {name=x27
}
C {devices/lab_pin.sym} 1360 290 0 0 {name=p42 sig_type=std_logic lab=VDD
}
C {devices/lab_pin.sym} 1480 290 2 0 {name=p70 sig_type=std_logic lab=VSS
}
C {devices/lab_pin.sym} 1390 250 0 0 {name=p71 sig_type=std_logic lab=S
}
C {devices/lab_pin.sym} 1470 250 2 0 {name=p224 sig_type=std_logic lab=Sb
}
C {devices/lab_pin.sym} 1250 70 0 0 {name=p237 sig_type=std_logic lab=noden}
C {Inverter.sym} -630 -370 0 0 {name=x2}
C {Inverter.sym} -490 -370 0 0 {name=x3}
C {Inverter.sym} -310 -370 0 0 {name=x4}
C {Inverter.sym} -170 -370 0 0 {name=x5}
C {Inverter.sym} 10 -370 0 0 {name=x6}
C {Inverter.sym} 150 -370 0 0 {name=x7}
C {Inverter.sym} 340 -370 0 0 {name=x8}
C {Inverter.sym} 480 -370 0 0 {name=x9}
C {Inverter.sym} 360 -500 2 0 {name=x10}
C {Inverter.sym} 220 -500 2 0 {name=x11}
C {Inverter.sym} 40 -500 2 0 {name=x12}
C {Inverter.sym} -100 -500 2 0 {name=x13}
C {Inverter.sym} -280 -500 2 0 {name=x14}
C {Inverter.sym} -420 -500 2 0 {name=x15}
C {Inverter.sym} -610 -500 2 0 {name=x16}
C {Inverter.sym} -750 -500 2 0 {name=x17}
C {Inverter.sym} -630 -620 0 0 {name=x18}
C {Inverter.sym} -490 -620 0 0 {name=x19}
C {Inverter.sym} -310 -620 0 0 {name=x20}
C {Inverter.sym} -170 -620 0 0 {name=x21}
C {Inverter.sym} 10 -620 0 0 {name=x22}
C {Inverter.sym} 150 -620 0 0 {name=x23}
C {Inverter.sym} 340 -620 0 0 {name=x24}
C {Inverter.sym} 480 -620 0 0 {name=x25}
C {devices/lab_pin.sym} -690 -440 0 0 {name=p238 sig_type=std_logic lab=VDD}
C {devices/lab_pin.sym} -690 -680 0 0 {name=p239 sig_type=std_logic lab=VDD}
C {devices/lab_pin.sym} -600 -370 1 0 {name=p240 sig_type=std_logic lab=db0}
C {devices/lab_pin.sym} -460 -370 1 0 {name=p241 sig_type=std_logic lab=d0}
C {devices/lab_pin.sym} -130 -370 1 0 {name=p242 sig_type=std_logic lab=d1}
C {devices/lab_pin.sym} -280 -370 1 0 {name=p243 sig_type=std_logic lab=db1}
C {devices/lab_pin.sym} 190 -370 1 0 {name=p244 sig_type=std_logic lab=d2}
C {devices/lab_pin.sym} 40 -370 1 0 {name=p245 sig_type=std_logic lab=db2}
C {devices/lab_pin.sym} 370 -370 1 0 {name=p246 sig_type=std_logic lab=db3}
C {devices/lab_pin.sym} 520 -370 2 0 {name=p247 sig_type=std_logic lab=d3}
C {devices/lab_pin.sym} 190 -500 3 0 {name=p248 sig_type=std_logic lab=d4}
C {devices/lab_pin.sym} 330 -500 3 0 {name=p249 sig_type=std_logic lab=db4}
C {devices/lab_pin.sym} -130 -500 3 0 {name=p250 sig_type=std_logic lab=d5}
C {devices/lab_pin.sym} 10 -500 3 0 {name=p251 sig_type=std_logic lab=db5}
C {devices/lab_pin.sym} -450 -500 3 0 {name=p252 sig_type=std_logic lab=d6}
C {devices/lab_pin.sym} -310 -500 3 0 {name=p253 sig_type=std_logic lab=db6}
C {devices/lab_pin.sym} -780 -500 3 0 {name=p254 sig_type=std_logic lab=d7}
C {devices/lab_pin.sym} -640 -500 3 0 {name=p255 sig_type=std_logic lab=db7}
C {devices/lab_pin.sym} -460 -620 3 0 {name=p256 sig_type=std_logic lab=d8}
C {devices/lab_pin.sym} -600 -620 3 0 {name=p257 sig_type=std_logic lab=db8}
C {devices/lab_pin.sym} -140 -620 3 0 {name=p258 sig_type=std_logic lab=d9}
C {devices/lab_pin.sym} -280 -620 3 0 {name=p259 sig_type=std_logic lab=db9}
C {devices/lab_pin.sym} 40 -620 3 0 {name=p260 sig_type=std_logic lab=db10}
C {devices/lab_pin.sym} 180 -620 3 0 {name=p261 sig_type=std_logic lab=d10}
C {devices/lab_pin.sym} 370 -620 3 0 {name=p262 sig_type=std_logic lab=db11}
C {devices/lab_pin.sym} 510 -620 3 0 {name=p263 sig_type=std_logic lab=d11}
C {devices/lab_pin.sym} -760 -370 0 0 {name=p264 sig_type=std_logic lab=di0}
C {devices/lab_pin.sym} -420 -370 1 0 {name=p265 sig_type=std_logic lab=di1}
C {devices/lab_pin.sym} -100 -370 1 0 {name=p266 sig_type=std_logic lab=di2}
C {devices/lab_pin.sym} 220 -370 1 0 {name=p267 sig_type=std_logic lab=di3}
C {devices/lab_pin.sym} 480 -500 1 0 {name=p268 sig_type=std_logic lab=di4}
C {devices/lab_pin.sym} 160 -500 1 0 {name=p269 sig_type=std_logic lab=di5}
C {devices/lab_pin.sym} -170 -500 1 0 {name=p270 sig_type=std_logic lab=di6}
C {devices/lab_pin.sym} -490 -500 1 0 {name=p271 sig_type=std_logic lab=di7}
C {devices/lab_pin.sym} -750 -620 1 0 {name=p272 sig_type=std_logic lab=di8}
C {devices/lab_pin.sym} -420 -620 1 0 {name=p273 sig_type=std_logic lab=di9}
C {devices/lab_pin.sym} -100 -620 1 0 {name=p274 sig_type=std_logic lab=di10}
C {devices/lab_pin.sym} 230 -620 1 0 {name=p275 sig_type=std_logic lab=di11}
C {devices/lab_pin.sym} -690 -310 0 0 {name=p276 sig_type=std_logic lab=VSS}
C {devices/lab_pin.sym} -690 -570 0 0 {name=p277 sig_type=std_logic lab=VSS}
C {transmission_gate.sym} 1680 120 1 0 {name=x28}
C {transmission_gate.sym} 1680 390 3 0 {name=x29}
C {devices/lab_pin.sym} 1590 440 0 0 {name=p41 sig_type=std_logic lab=VDD}
C {devices/lab_pin.sym} 1770 70 2 0 {name=p43 sig_type=std_logic lab=VDD}
C {devices/lab_pin.sym} 1590 70 0 0 {name=p72 sig_type=std_logic lab=VSS}
C {devices/lab_pin.sym} 1770 440 2 0 {name=p73 sig_type=std_logic lab=VSS}
C {devices/lab_pin.sym} 1680 20 2 0 {name=p74 sig_type=std_logic lab=Vcm}
C {devices/lab_pin.sym} 1680 500 2 0 {name=p75 sig_type=std_logic lab=Vcm}
C {devices/lab_pin.sym} 1740 110 2 0 {name=p222 sig_type=std_logic lab=S}
C {devices/lab_pin.sym} 1610 400 0 0 {name=p223 sig_type=std_logic lab=S}
C {devices/lab_pin.sym} 1600 110 0 0 {name=p225 sig_type=std_logic lab=Sb}
C {devices/lab_pin.sym} 1760 400 2 0 {name=p226 sig_type=std_logic lab=Sb}
C {Network_Switch.sym} 1230 -20 0 0 {name=x1}
C {devices/lab_pin.sym} 1170 -50 0 0 {name=p20 sig_type=std_logic lab=VDD}
C {devices/lab_pin.sym} 1170 10 0 0 {name=p28 sig_type=std_logic lab=VSS}
C {devices/lab_pin.sym} 1170 -30 2 1 {name=p83 sig_type=std_logic lab=S}
C {devices/lab_pin.sym} 1170 -10 2 1 {name=p85 sig_type=std_logic lab=Sb}
C {devices/lab_pin.sym} 1300 -30 2 0 {name=p87 sig_type=std_logic lab=VDD}
C {devices/lab_pin.sym} 1300 -10 2 0 {name=p89 sig_type=std_logic lab=VSS}
C {Network_Switch.sym} 1230 520 2 1 {name=x26}
C {devices/lab_pin.sym} 1170 550 2 1 {name=p91 sig_type=std_logic lab=VDD}
C {devices/lab_pin.sym} 1170 490 2 1 {name=p93 sig_type=std_logic lab=VSS}
C {devices/lab_pin.sym} 1170 530 0 0 {name=p95 sig_type=std_logic lab=S}
C {devices/lab_pin.sym} 1170 510 0 0 {name=p97 sig_type=std_logic lab=Sb}
C {devices/lab_pin.sym} 1300 530 0 1 {name=p99 sig_type=std_logic lab=VDD}
C {devices/lab_pin.sym} 1300 510 0 1 {name=p101 sig_type=std_logic lab=VSS}
C {bootstrapped_switch.sym} -1540 -160 0 0 {name=x54}
C {bootstrapped_switch.sym} -1570 680 0 0 {name=x55}
C {devices/lab_pin.sym} 1250 420 0 0 {name=p103 sig_type=std_logic lab=nodep}
C {devices/capa.sym} 1060 380 0 1 {name=C27
m=1
value=\{Cu\}
footprint=1206
device="ceramic capacitor"}
C {devices/capa.sym} 880 380 0 1 {name=C28
m=1
value=\{2*Cu\}
footprint=1206
device="ceramic capacitor"}
C {devices/capa.sym} 700 380 0 1 {name=C29
m=1
value=\{4*Cu\}
footprint=1206
device="ceramic capacitor"}
C {devices/capa.sym} 520 380 0 1 {name=C30
m=1
value=\{8*Cu\}
footprint=1206
device="ceramic capacitor"}
C {devices/capa.sym} 340 380 0 1 {name=C31
m=1
value=\{16*Cu\}
footprint=1206
device="ceramic capacitor"}
C {devices/capa.sym} 160 380 0 1 {name=C32
m=1
value=\{32*Cu\}
footprint=1206
device="ceramic capacitor"}
C {devices/capa.sym} -70 380 0 1 {name=C33
m=1
value=\{64*Cu\}
footprint=1206
device="ceramic capacitor"}
C {devices/capa.sym} -250 380 0 1 {name=C34
m=1
value=\{128*Cu\}
footprint=1206
device="ceramic capacitor"}
C {devices/capa.sym} -430 380 0 1 {name=C35
m=1
value=\{256*Cu\}
footprint=1206
device="ceramic capacitor"}
C {devices/capa.sym} -610 380 0 1 {name=C36
m=1
value=\{512*Cu\}
footprint=1206
device="ceramic capacitor"}
C {devices/capa.sym} -790 380 0 1 {name=C37
m=1
value=\{1024*Cu\}
footprint=1206
device="ceramic capacitor"}
C {devices/capa.sym} -970 380 0 1 {name=C38
m=1
value=\{2048*Cu\}
footprint=1206
device="ceramic capacitor"}
C {devices/capa.sym} 1250 380 0 0 {name=C39
m=1
value=\{Cu\}
footprint=1206
device="ceramic capacitor"}
C {devices/capa.sym} 1060 120 0 1 {name=C40
m=1
value=\{Cu\}
footprint=1206
device="ceramic capacitor"}
C {devices/capa.sym} 880 120 0 1 {name=C41
m=1
value=\{2*Cu\}
footprint=1206
device="ceramic capacitor"}
C {devices/capa.sym} 700 120 0 1 {name=C42
m=1
value=\{4*Cu\}
footprint=1206
device="ceramic capacitor"}
C {devices/capa.sym} 520 120 0 1 {name=C43
m=1
value=\{8*Cu\}
footprint=1206
device="ceramic capacitor"}
C {devices/capa.sym} 340 120 0 1 {name=C44
m=1
value=\{16*Cu\}
footprint=1206
device="ceramic capacitor"}
C {devices/capa.sym} 160 120 0 1 {name=C45
m=1
value=\{32*Cu\}
footprint=1206
device="ceramic capacitor"}
C {devices/capa.sym} -70 120 0 1 {name=C46
m=1
value=\{64*Cu\}
footprint=1206
device="ceramic capacitor"}
C {devices/capa.sym} -250 120 0 1 {name=C47
m=1
value=\{128*Cu\}
footprint=1206
device="ceramic capacitor"}
C {devices/capa.sym} -430 120 0 1 {name=C48
m=1
value=\{256*Cu\}
footprint=1206
device="ceramic capacitor"}
C {devices/capa.sym} -610 120 0 1 {name=C49
m=1
value=\{512*Cu\}
footprint=1206
device="ceramic capacitor"}
C {devices/capa.sym} -790 120 0 1 {name=C50
m=1
value=\{1024*Cu\}
footprint=1206
device="ceramic capacitor"}
C {devices/capa.sym} -970 120 0 1 {name=C51
m=1
value=\{2048*Cu\}
footprint=1206
device="ceramic capacitor"}
C {devices/capa.sym} 1250 120 0 0 {name=C52
m=1
value=\{Cu\}
footprint=1206
device="ceramic capacitor"}
C {devices/lab_pin.sym} -970 70 0 0 {name=p105 sig_type=std_logic lab=Vc1n}
C {devices/lab_pin.sym} -970 420 0 0 {name=p107 sig_type=std_logic lab=Vc1p}
C {devices/lab_pin.sym} -790 70 0 0 {name=p109 sig_type=std_logic lab=Vc2n}
C {devices/lab_pin.sym} -790 420 0 0 {name=p111 sig_type=std_logic lab=Vc2p}
C {sky130_fd_pr/cap_mim_m3_1.sym} 1250 250 0 0 {name=C1 model=cap_mim_m3_1 W=0.01 L=0.01 MF=1 spiceprefix=X}
C {sky130_fd_pr/cap_mim_m3_1.sym} 1060 250 0 0 {name=C2 model=cap_mim_m3_1 W=1 L=1 MF=1 spiceprefix=X}
C {sky130_fd_pr/cap_mim_m3_1.sym} 880 250 0 0 {name=C3 model=cap_mim_m3_1 W=1 L=1 MF=1 spiceprefix=X}
C {sky130_fd_pr/cap_mim_m3_1.sym} 700 250 0 0 {name=C4 model=cap_mim_m3_1 W=1 L=1 MF=1 spiceprefix=X}
C {sky130_fd_pr/cap_mim_m3_1.sym} 520 250 0 0 {name=C5 model=cap_mim_m3_1 W=1 L=1 MF=1 spiceprefix=X}
C {sky130_fd_pr/cap_mim_m3_1.sym} 340 250 0 0 {name=C6 model=cap_mim_m3_1 W=1 L=1 MF=1 spiceprefix=X}
C {sky130_fd_pr/cap_mim_m3_1.sym} 160 250 0 0 {name=C7 model=cap_mim_m3_1 W=1 L=1 MF=1 spiceprefix=X}
C {sky130_fd_pr/cap_mim_m3_1.sym} -70 250 0 0 {name=C8 model=cap_mim_m3_1 W=1 L=1 MF=1 spiceprefix=X}
C {sky130_fd_pr/cap_mim_m3_1.sym} -250 250 0 0 {name=C9 model=cap_mim_m3_1 W=1 L=1 MF=1 spiceprefix=X}
C {sky130_fd_pr/cap_mim_m3_1.sym} -430 250 0 0 {name=C10 model=cap_mim_m3_1 W=1 L=1 MF=1 spiceprefix=X}
C {sky130_fd_pr/cap_mim_m3_1.sym} -610 250 0 0 {name=C11 model=cap_mim_m3_1 W=1 L=1 MF=1 spiceprefix=X}
C {sky130_fd_pr/cap_mim_m3_1.sym} -790 250 0 0 {name=C12 model=cap_mim_m3_1 W=1 L=1 MF=1 spiceprefix=X}
C {sky130_fd_pr/cap_mim_m3_1.sym} -970 250 0 0 {name=C13 model=cap_mim_m3_1 W=1 L=1 MF=1 spiceprefix=X}
